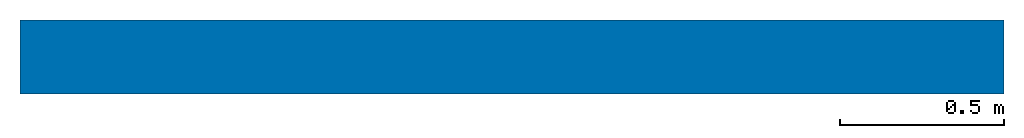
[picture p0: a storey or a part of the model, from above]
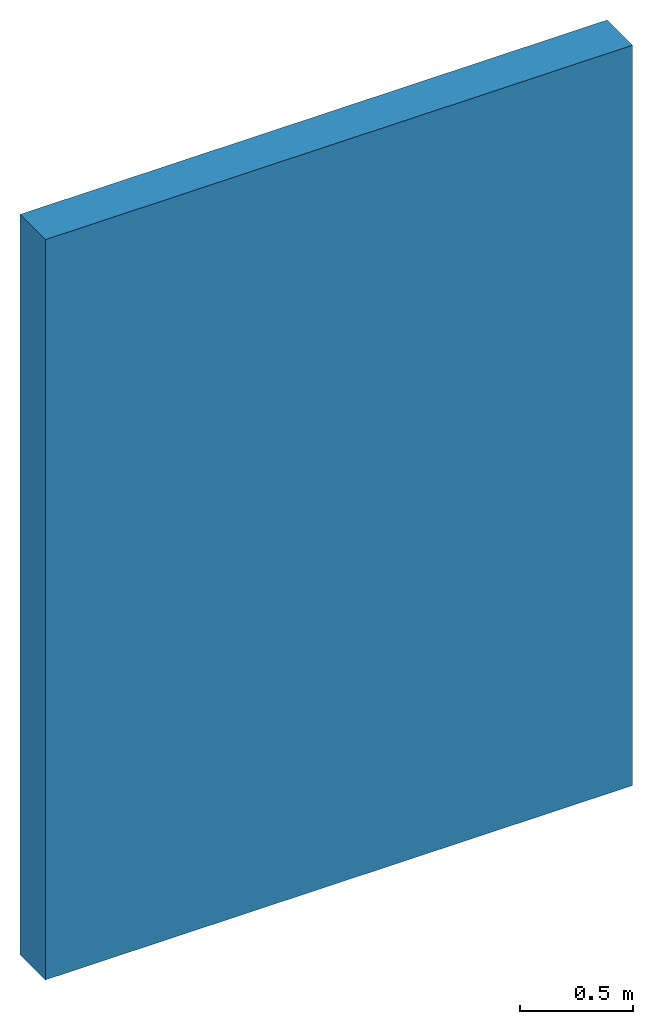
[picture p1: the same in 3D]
Properties of the parts of a building model (IFC2X3)

# File
Description: ViewDefinition [CoordinationView_V2.0, QuantityTakeOffAddOnView]
File name: 0001
Time: 2018-04-04T18:20:35
Written by: The EXPRESS Data Manager Version 5.02.0100.07 : 28 Aug 2013
Made in: 20170419_0315(x64) - Exporter 17.0.1128.0 - Альтернативный интерфейс 17.17.0.0
Comment: STEP Physical File produced by: The EXPRESS Data Manager Version 5.02.0100.07 : 28 Aug 2013 * Module: EDMstepFileFactory/EDMstandAlone * Creation date: Wed Apr 04 18:20:35 2018 * Host: w13mim038 * Database: C:\Users\odegov.s\AppData\Local\Temp\{2AB5C1E6-69CD-4EF3-B893-4328DA6E1BB6}\ifc * Database version: 5507 * Database creation date: Wed Apr 04 18:20:35 2018 * Schema: IFC2X3 * Model: DataRepository.ifc * Model creation date: Wed Apr 04 18:20:35 2018 * Header model: DataRepository.ifc_HeaderModel * Header model creation date: Wed Apr 04 18:20:35 2018 * EDMuser: sdai-user * EDMgroup: sdai-group * License ID and type: 5605 : Permanent license. Expiry date: * EDMstepFileFactory options: 020000

# IfcProject, 0001
LongName: Наименование проекта; Phase: Статус проекта

# IfcSite, Default
RefLatitude: 55, 44, 59, 999999; RefLongitude: 37, 42, 0, 2746; RefElevation: 0 mm
Прочее - Адрес проекта: Укажите адрес; Дата утверждения проекта: Дата выпуска; Заказчик: Владелец; Категория: Сведения о проекте; Наименование проекта: Наименование проекта; Номер проекта: 0001; Статус проекта: Статус проекта

# IfcBuilding
Pset_BuildingCommon - NumberOfStoreys: 1
Прочее - Категория: Сведения о проекте; Адрес проекта: Укажите адрес; Дата утверждения проекта: Дата выпуска; Заказчик: Владелец; Наименование проекта: Наименование проекта; Номер проекта: 0001; Статус проекта: Статус проекта

# IfcBuildingStorey, Уровень 1
LongName: Уровень 1; Elevation: 0 mm
Прочее - Категория: Уровни; Имя семейства: Уровень; Код типа: Уровень: Верхний брус 8 мм; Семейство: Уровень: Верхний брус 8 мм; Семейство и типоразмер: Уровень: Верхний брус 8 мм; Тип: Уровень: Верхний брус 8 мм
Зависимости - Фасад: 0 mm; Базовая отметка: Базовая точка проекта
Идентификация - Несущие конструкции: no; Имя: Уровень 1; Построение этажа: yes; Имя типа: Верхний брус 8 мм
Размеры - Расчетная высота: 0 mm
Графика - Вес линий: 1; Обозначение: Заголовок уровня - Окружность: Заголовок уровня - Окружность; Образец линий: Центр; Стандартное обозначение второго конца: yes; Стандартное обозначение первого конца: no; Цвет: 0

# IfcWallStandardCase: Базовая стена:Перегородка КНАУФ W145 Применение внутри здания MW100/50 ПН100х40 с двуслойной КНАУФ-Сапфир+ГВЛ, Базовая стена:Перегородка КНАУФ W145 Применение внутри здания MW100/50 ПН100х40 с двуслойной КНАУФ-Сапфир+ГВЛ:422572
In: Уровень 1
Type - PredefinedType: STANDARD; Material: КНАУФ-Сапфир 12.5 mm, КНАУФ-Сапфир 12.5 mm, КНАУФ-суперлист влагостойкий 12.5 mm, КНАУФ-суперлист влагостойкий 12.5 mm, Luft 25 mm, КНАУФ-профиль+мин.вата 75@600mm 75 mm, Luft 25 mm, КНАУФ-суперлист влагостойкий 12.5 mm, КНАУФ-суперлист влагостойкий 12.5 mm, КНАУФ-Сапфир 12.5 mm, КНАУФ-Сапфир 12.5 mm
Type - Графика - Цвет штриховки при низкой детализации: 0
Type - Идентификация - Имя типа: Перегородка КНАУФ W145 Применение внутри здания MW100/50 ПН100х40 с двуслойной КНАУФ-Сапфир+ГВЛ
Type - Материалы и отделка - Материал несущих конструкций: КНАУФ-профиль+мин.вата 75@600mm
Type - Прочее - Категория: Стены; Имя семейства: Базовая стена
Type - Свойства аналитической модели - Коэффициент поглощения: 0.7; Коэффициент теплопередачи (U): 0.237053; Теплоемкость: 58060.2; Термостойкость: 4.21847; Шероховатость: 3
Type - Строительство - Гипсовая строительная плита ГСП-DFH3IR (Knauf - Сапфир): 4.5; Дихтунгсбанд 95 мм 30м (б) серый: 0.16; Дюбель с шурупом 6x40 (200): 0.02; КСЛВ ФК 2500х1200х12,5 (40): 4; Лента "Курт" для швов 25 м: 0.16; Минераловатная теплоизоляция 50мм 35кг/м3: 4.5; Огибание в местах вставки элементов: Нет; Огибание в торцах стен: Нет; Профиль металлический MW-Profil 100/50: 4; Профиль направляющий ПН100/40: 1.4; Саморез XTN 3,9х23 мм: 0.018; Саморез XTN 3,9х55 мм: 0.0129; Саморез XTN 3,9х65 мм: 0.01; Тифенгрунд 10л (33): 0.02; Функция: Внутренние слои; Ширина: 225 mm; Шпаклевка КНАУФ-Унифолт: 0.112; Шуруп д/ГВЛ 3.9х25 (1000): 0.018; Шуруп д/ГВЛ 3.9х45 (500): 0.036
BaseQuantities - Height: 4000 mm; Length: 3000 mm; Width: 225 mm; GrossFootprintArea: 0.675 m2; GrossSideArea: 12 m2; GrossVolume: 2.7 m3
Зависимости - Базовая зависимость: Уровень: Уровень 1; Граница помещения: yes; Линия привязки: Осевая линия стены; Неприсоединенная высота: 4000 mm; Примыкание сверху: no; Примыкание снизу: no; Размер выступа сверху: 0 mm; Размер выступа снизу: 0 mm; Связь с формообразующим элементом: no; Смещение сверху: 0 mm; Смещение снизу: 0 mm
Несущие конструкции - Включить аналитическую модель: no; Использование в конструкции: Ненесущая; Несущие конструкции: no
Прочее - Код типа: Базовая стена: Перегородка КНАУФ W145 Применение внутри здания MW100/50 ПН100х40 с двуслойной КНАУФ-Сапфир+ГВЛ; Семейство: Базовая стена: Перегородка КНАУФ W145 Применение внутри здания MW100/50 ПН100х40 с двуслойной КНАУФ-Сапфир+ГВЛ; Семейство и типоразмер: Базовая стена: Перегородка КНАУФ W145 Применение внутри здания MW100/50 ПН100х40 с двуслойной КНАУФ-Сапфир+ГВЛ; Тип: Базовая стена: Перегородка КНАУФ W145 Применение внутри здания MW100/50 ПН100х40 с двуслойной КНАУФ-Сапфир+ГВЛ
Размеры - Длина: 3000 mm; Объем: 2.7 m3; Площадь: 12 m2
Стадии - Стадия возведения: Новая конструкция
Pset_WallCommon - Reference: Перегородка КНАУФ W145 Применение внутри здания MW100/50 ПН100х40 с двуслойной КНАУФ-Сапфир+ГВЛ; LoadBearing: no; ExtendToStructure: no; IsExternal: no; ThermalTransmittance: 0.237053 kg/K/s3
